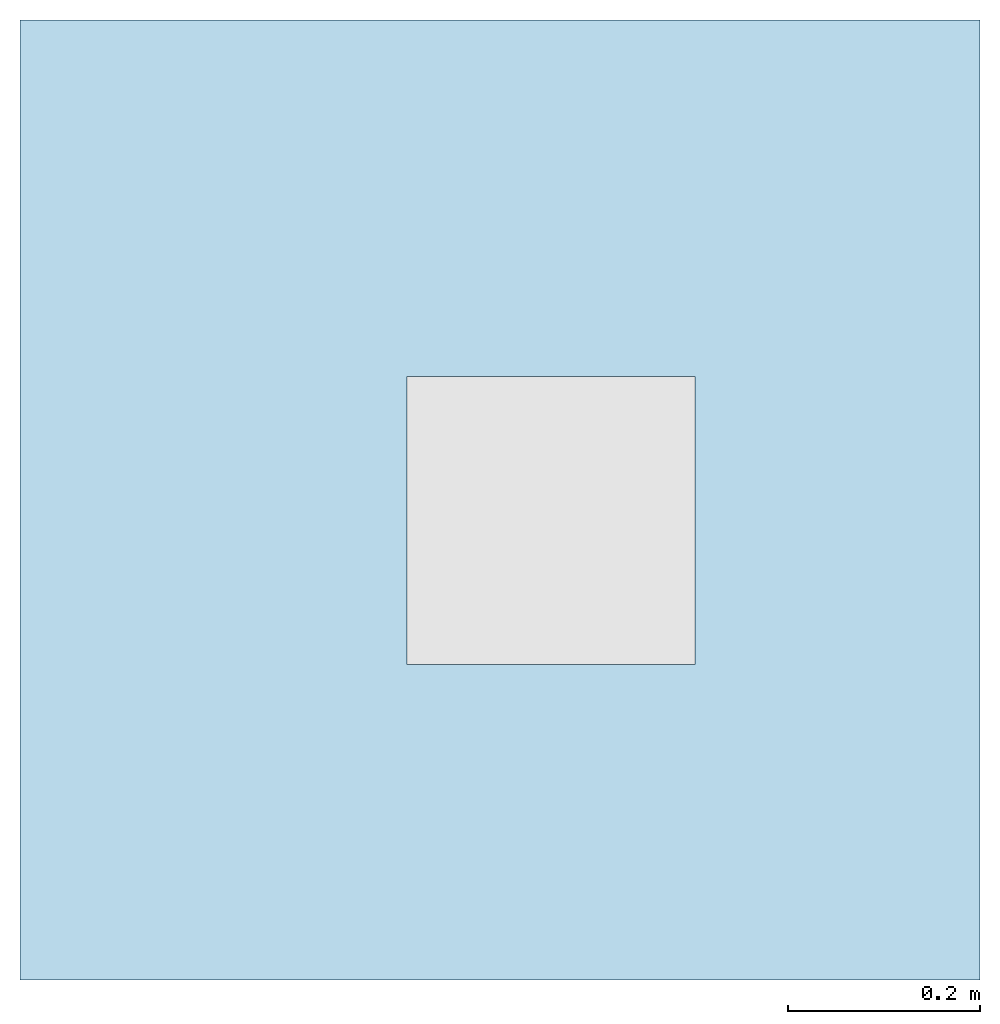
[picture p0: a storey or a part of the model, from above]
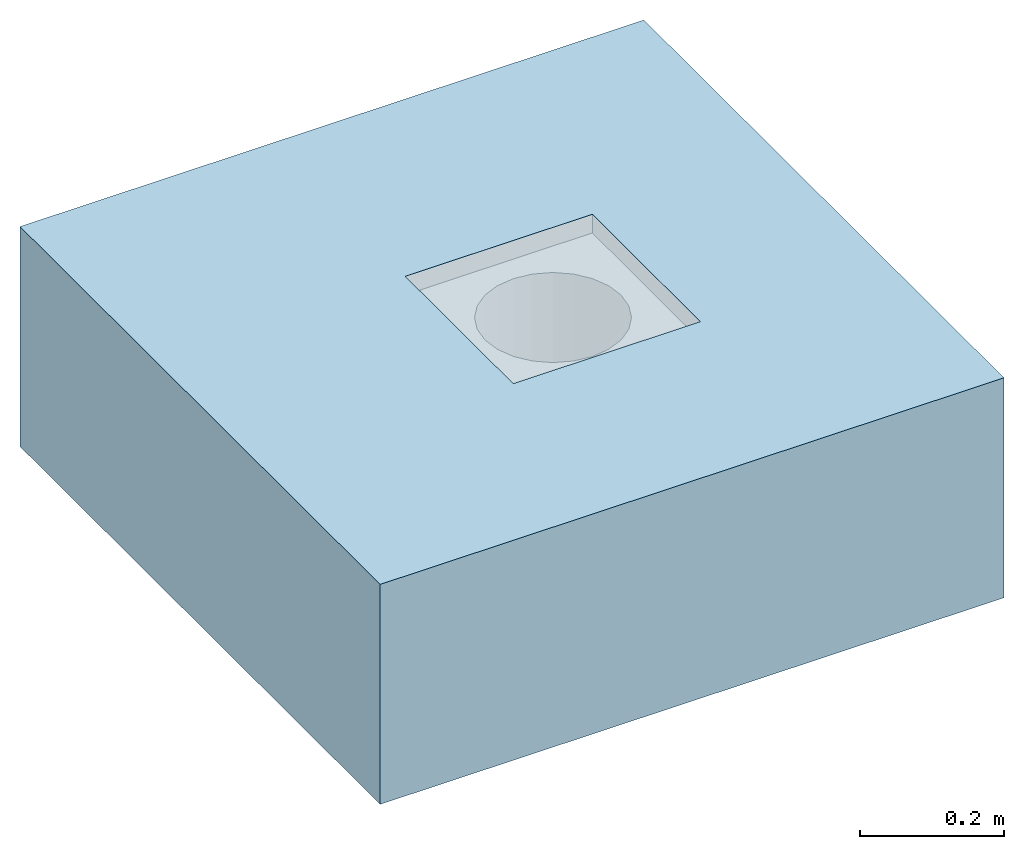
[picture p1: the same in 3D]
Properties of the parts of a building model (IFC2X3)

# File
Description: ViewDefinition [CoordinationView]
File name: Project Number
Time: 2014-10-30T17:55:45
Written by: The EXPRESS Data Manager Version 5.01.0100.02.64mod : 6 Jun 2012
Made in: 20130308_1515(x64) - Exporter 2014.0.2013.0308 - Default UI
Comment: STEP Physical File produced by: The EXPRESS Data Manager Version 5.01.0100.02.64mod : 6 Jun 2012 * Module: EDMstepFileFactory/EDMstandAlone * Creation date: Thu Oct 30 17:55:45 2014 * Host: IN-BLR-PC-0012 * Database: C:\Users\pponnur\AppData\Local\Temp\{62BEDBF9-6C0C-4B2B-9171-81A96D1CF43F}\ifc * Database version: 5507 * Database creation date: Thu Oct 30 17:55:44 2014 * Schema: IFC2X3 * Model: DataRepository.ifc * Model creation date: Thu Oct 30 17:55:44 2014 * Header model: DataRepository.ifc_HeaderModel * Header model creation date: Thu Oct 30 17:55:44 2014 * EDMuser: sdai-user * EDMgroup: sdai-group * License ID and type: 5605 : Permanent license. Expiry date: * EDMstepFileFactory options: 020000

# IfcProject, Project Number
LongName: Project Name; Phase: Project Status

# IfcSite, Default
RefLatitude: 42, 21, 30, 344238; RefLongitude: -71, -3, -35, -194702; RefElevation: 0 mm

# IfcBuilding
Pset_BuildingCommon - NumberOfStoreys: 1
Other - Client Name: Owner; Project Issue Date: Issue Date; Project Status: Project Status; Project Address: Enter address here; Project Name: Project Name; Project Number: Project Number

# IfcBuildingStorey, Level 1
LongName: Level 1; Elevation: 0 mm
Constraints - Elevation Base: Project Base Point; Elevation: 0 mm
Graphics - Symbol at End 1 Default: no; Color: 0; Symbol at End 2 Default: yes; Symbol: Level Head - Circle: Level Head - Circle; Line Weight: 1; Line Pattern: Grid Line 1/2"
Identity Data - Building Story: yes; Name: Level 1; Structural: no
Dimensions - Computation Height: 0 mm

# IfcFlowTerminal: 408007 - Fixed Height - 300 x 300mm Top Size - 160mm Outlet, ACO BD Gully 218 - Fixed Height - Vertical Outlet:408007 - Fixed Height - 300 x 300mm Top Size - 160mm Outlet:189137
In: Level 1
Material: Stainless Steel AISI 304, Rubber, Nitrile
Dimensions - Gully Void Depth: -275 mm; Outlet Depth: 275 mm; Outlet Radius: 80 mm; Gully Top Opening: 12.594 mm; Void Radius: 81 mm
Construction - 408036 - 268 x 268mm - Quadrato Grating - Brushed - Stainless steel 304: no; 408040 - 268 x 268mm - HeelSafe Grating - Brushed - Stainless Steel 304: no; 408035 - 268 x 268mm - Mesh Grating - Plain - Stainless Steel 304: no; 408222 - Silt Basket: yes; 408034 - 268 x 268mm - Mesh Grating - Slip Resistant - Stainless Steel 304: no; 408042 - 268 x 268mm - Volcano Grating - Slip Resistant - Stainless Steel 304: no; 408038 - 268 x 268mm - Ladder Grating - Plain - Stainless Steel 304: no; 408045 - 268 x 268mm - Ladder Grating - Plain - Stainless Steel 304: no; 408039 - 268 x 268mm - Slot Cover - Plain - Stainless Steel 304: no; 408041 - 268 x 268mm - Arla Grating - Slip Resistant - Stainless Steel 304: no; 408037 - 268 x 268mm - Ladder Grating - Slip Resistant - Stainless steel 304: no; 408220 - Foul Air Trap & 408221 - Foul Air Trap Support Ring: yes; 160mm Dia Outlet: yes; 110mm Dia Outlet: no
Identity Data - Mark: 2; E-mail Technical: abdtechnical@aco.co.uk; Fax: +44 (0)1462 851490; Website: www.acobd.com; Water Marked With: BIM Manager Premium Suite; Watermarked By: www.acobd.com; Water Mark 1: This file is the property of ACO Technologies PLC; Water Mark 2: This file is water marked and users are prohibited to reproduce, adapt, distribute this information; E-mail Sales: abdcommercial@aco.co.uk; Manufacturer: ACO Building Drainage; Address: ACO Business Centre, Caxton Road, Bedford, MK41 0LF; Telephone: +44 (0)1462 816666
Constraints - Level: Level: Level 1
Phasing - Phase Created: New Construction
Mechanical - System Classification: Sanitary
Pset_ManufacturerTypeInformation - Manufacturer: ACO Building Drainage
Model Properties - Product Code 408220: Foul Air Trap - Stainless Steel 304; Grating Product Code 408041: Load Class L15 (EN 1253) - Arla Grating - Slip Resistant - Stainles steel 1.4301 (EN 10088) - 268 x 268 x 30mm; Product Code 408221: Foul Air Trap Support Ring - Nitrile; Grating Product Code 408034: Load Class L15 (EN 1253) - Mesh Grating - Slip Resistant - Stainles steel 1.4301 (EN 10088) - 268 x 268 x 30mm; Grating Product Code 408036: Load Class L15 (EN 1253) - Quadrato Grating - Brushed - Stainles steel 1.4301 (EN 10088) - 268 x 268 x 30mm; Grating Product Code 408038: Load Class M125 (EN 1253) - Ladder Grating -Plain - Stainles steel 1.4301 (EN 10088) - 268 x 268 x 30mm; Grating Product Code 408037: Load Class M125 (EN 1253) - Ladder Grating - Slip Resistant - Stainles steel 1.4301 (EN 10088) - 268 x 268 x 30mm; Grating Product Code 408045: Load Class C250 (EN 1253) - Ladder Grating - Plain - Stainles steel 1.4301 (EN 10088) - 268 x 268 x 30mm; Grating Product Code 408042: Load Class M125 (EN 1253) - Volcano Grating - Slip Resistant - Stainles steel 1.4301 (EN 10088) - 268 x 268 x 30mm; Grating Product Code 408035: Load Class L15 (EN 1253) - Mesh Grating – Plain - Stainles steel 1.4301 (EN 10088) - 268 x 268 x 30mm; Product Code 408222: Silt Basket - Stainless Steel 304; Grating Product Code 408039: Load Class M125 (EN 1253) - Slot Cover - Plain - Stainles steel 1.4301 (EN 10088) - 268 x 268 x 30mm; Grating Product Code 408040: Load Class L15 (EN 1253) - Heelsafe Grating - Brushed - Stainles steel 1.4301 (EN 10088) - 268 x 268 x 30mm
General - Gully Product Description: ACO gully 218 fixed height 300x300/DN 160 vertical with foul air trap; Foul Air Trap Seal Recycled Material Content: 0%; Gully Recycled Material Content: 20 - 30 %; Maintenance guidelines: http://issuu.com/acobuildingdrainage/docs/120820112708-138bdc871b784edfa2b6b8197acfd881?e=0; Product Standard: EN 1253; Flow Rate (l/s): 5.0 l/s; Price: POA - contact ACO; Gully Recyclable: Fully recyclable; Product Type: Point Drainage; Gully Material: Stainless steel 1.4301 (EN 10088); Outlet Diameter (mm): 160; Gully Colour: passivated stainless steel surface ( matt grey); Foul Air Trap Seal Colour: Black; Installation guidelines: http://issuu.com/acobuildingdrainage/docs/120820112708-138bdc871b784edfa2b6b8197acfd881?e=0; NBS Specification: R11 ABOVE GROUND FOUL DRAINAGE SYSTEMS : Clause 315; Gully Product Code: 408007; Load Class: A15 - C250 (EN 1253); Gully top Grate size (mm): 300 x 300; Product Range: ACO gully 218; Foul Air Trap Seal Material: NBR; Foul Air Trap Seal Recyclable: Fully recyclable

# IfcOpeningElement: Recess
In: Level 1
Phasing - Phase Created: New Construction
Constraints - Room Bounding: yes; Related to Mass: no; Height Offset From Level: 0 mm; Level: Level: Level 1
Dimensions - Area: 10.7639 ft2; Perimeter: 4000 mm; Volume: 12.7896 ft3; Thickness: 372.8 mm
Structural - Enable Analytical Model: no; Structural: no
Identity Data - Assembly Description: Floor Construction; Assembly Code: B1010
Graphics - Coarse Scale Fill Color: 0
Construction - Function: Interior; Default Thickness: 372.8 mm
Analytical Properties - Thermal Resistance (R): 0.641509; Thermal mass: 53301.1; Absorptance: 0.7; Heat Transfer Coefficient (U): 1.55882; Roughness: 3

# IfcSlab: Floor:Generic - 12", Floor:Generic - 12":184145
In: Level 1
PredefinedType: FLOOR; Material: Plywood, Sheathing 68 mm, Default Floor 304.8 mm
Phasing - Phase Created: New Construction
Constraints - Room Bounding: yes; Related to Mass: no; Height Offset From Level: 0 mm; Level: Level: Level 1
Dimensions - Area: 10.7639 ft2; Perimeter: 4000 mm; Volume: 12.7896 ft3; Thickness: 372.8 mm
Structural - Enable Analytical Model: no; Structural: no
Pset_SlabCommon - Reference: Generic - 12"; IsExternal: no; LoadBearing: yes; ThermalTransmittance: 1.55882 kg/K/s3
Identity Data - Assembly Description: Floor Construction; Assembly Code: B1010
Graphics - Coarse Scale Fill Color: 0
Construction - Function: Interior; Default Thickness: 372.8 mm
Analytical Properties - Thermal Resistance (R): 0.641509; Thermal mass: 53301.1; Absorptance: 0.7; Heat Transfer Coefficient (U): 1.55882; Roughness: 3
